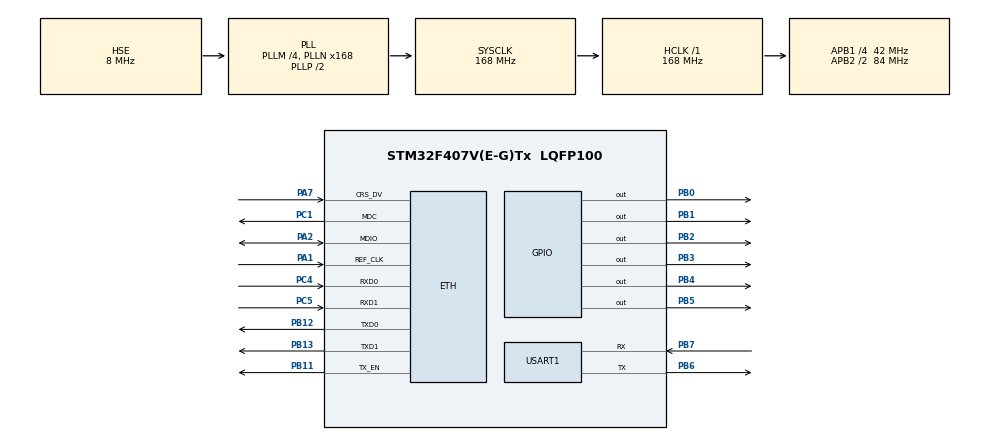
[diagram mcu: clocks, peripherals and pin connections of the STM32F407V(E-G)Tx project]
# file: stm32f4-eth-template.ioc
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ETH.MediaInterface=ETH_MEDIA_INTERFACE_RMII
LWIP.GATEWAY_ADDRESS=192.168.000.001
LWIP.IP_ADDRESS=192.168.000.122
LWIP.LWIP_DBG_OFF=0x00U
LWIP.LWIP_DBG_ON=0x80U
LWIP.LWIP_DHCP=0
LWIP.LWIP_FIONREAD_LINUXMODE=0
LWIP.LWIP_NETCONN=0
LWIP.LWIP_NETCONN_FULLDUPLEX=0
LWIP.LWIP_NETCONN_SEM_PER_THREAD=0
LWIP.LWIP_NETIF_LINK_CALLBACK=1
LWIP.LWIP_POSIX_SOCKETS_IO_NAMES=0
LWIP.LWIP_SOCKET=0
LWIP.LWIP_SOCKET_SET_ERRNO=0
LWIP.LWIP_SO_LINGER=0
LWIP.LWIP_SO_RCVBUF=0
LWIP.LWIP_SO_RCVTIMEO=0
LWIP.LWIP_SO_SNDRCVTIMEO_NONSTANDARD=0
LWIP.LWIP_SO_SNDTIMEO=0
LWIP.LWIP_TCPIP_TIMEOUT=0
LWIP.LWIP_TCP_KEEPALIVE=0
LWIP.LWIP_UDP=0
LWIP.MEM_SIZE=20000
LWIP.NETMASK_ADDRESS=255.255.255.000
LWIP.PBUF_POOL_BUFSIZE=1600
LWIP.SO_REUSE=0
LWIP.SO_REUSE_RXTOALL=0
LWIP.TCP_MSS=1460
LWIP.TCP_QUEUE_OOSEQ=0
LWIP.Version=v2.0.0_Cube
Mcu.Family=STM32F4
Mcu.Name=STM32F407V(E-G)Tx
Mcu.Package=LQFP100
NVIC.ETH_IRQn=true\:0\:0\:false\:false\:true
NVIC.ETH_WKUP_IRQn=true\:0\:0\:false\:false\:true
NVIC.PriorityGroup=NVIC_PRIORITYGROUP_4
PA1.Mode=RMII
PA1.Signal=ETH_REF_CLK
PA2.Mode=RMII
PA2.Signal=ETH_MDIO
PA7.Mode=RMII
PA7.Signal=ETH_CRS_DV
PB0.Signal=GPIO_Output
PB1.Signal=GPIO_Output
PB11.Mode=RMII
PB11.Signal=ETH_TX_EN
PB12.Mode=RMII
PB12.Signal=ETH_TXD0
PB13.Mode=RMII
PB13.Signal=ETH_TXD1
PB2.Signal=GPIO_Output
PB3.Signal=GPIO_Output
PB4.Signal=GPIO_Output
PB5.Signal=GPIO_Output
PB6.Mode=Asynchronous
PB6.Signal=USART1_TX
PB7.Mode=Asynchronous
PB7.Signal=USART1_RX
PC1.Mode=RMII
PC1.Signal=ETH_MDC
PC4.Mode=RMII
PC4.Signal=ETH_RXD0
PC5.Mode=RMII
PC5.Signal=ETH_RXD1
PH0-OSC_IN.Mode=HSE-External-Oscillator
PH0-OSC_IN.Signal=RCC_OSC_IN
PH1-OSC_OUT.Mode=HSE-External-Oscillator
PH1-OSC_OUT.Signal=RCC_OSC_OUT
ProjectManager.HeapSize=0x200
ProjectManager.StackSize=0x400
ProjectManager.TargetToolchain=EWARM
RCC.48MHZClocksFreq_Value=84000000
RCC.AHBFreq_Value=168000000
RCC.APB1CLKDivider=RCC_HCLK_DIV4
RCC.APB1Freq_Value=42000000
RCC.APB1TimFreq_Value=84000000
RCC.APB2CLKDivider=RCC_HCLK_DIV2
RCC.APB2Freq_Value=84000000
RCC.APB2TimFreq_Value=168000000
RCC.ClockTypeHCLK=RCC_CLOCKTYPE_HCLK
RCC.ClockTypePCLK1=RCC_CLOCKTYPE_PCLK1
RCC.ClockTypePCLK2=RCC_CLOCKTYPE_PCLK2
RCC.ClockTypeSysClk=RCC_CLOCKTYPE_SYSCLK
RCC.CortexFreq_Value=168000000
RCC.EnableExtClockForI2S=false
RCC.EnableHSE=true
RCC.EnableHSERTCDevisor=false
RCC.EnableLSE=false
RCC.EnableLSERTC=false
RCC.ExtClockEnable=false
RCC.HCLKFreq_Value=168000000
RCC.HSEState=RCC_HSE_ON
RCC.HSE_VALUE=8000000
RCC.HSIState=RCC_HSI_OFF
RCC.HSI_VALUE=16000000
RCC.I2SEnable=false
RCC.IWDGEnable=false
RCC.LSE_VALUE=32768
RCC.LSIState=RCC_LSI_OFF
RCC.MCO1OutPutEnable=false
RCC.MCO2OutPutEnable=false
RCC.OscillatorTypeHSE=RCC_OSCILLATORTYPE_HSE
RCC.PLLM=4
RCC.PLLN=168
RCC.PLLSource=RCC_PLLSOURCE_HSE
RCC.PLLSourceVirtual=RCC_PLLSOURCE_HSE
RCC.PLLState=RCC_PLL_ON
RCC.RNGEnable=false
RCC.RTCEnable=false
RCC.SDIOEnable=false
RCC.SYSCLKFreq_VALUE=168000000
RCC.SYSCLKSource=RCC_SYSCLKSOURCE_PLLCLK
RCC.USBFSEnable=false
RCC.USBHSEnable=false
RCC.VCOOutputFreq_Value=336000000
USART1.HwFlowCtl-Asynchronous=UART_HWCONTROL_NONE
USART1.VirtualMode=VM_ASYNC
VP_LWIP_VS_Enabled.Mode=Enabled
board=stm32f4-eth-template

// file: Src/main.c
/**
  ******************************************************************************
  * File Name          : main.c
  * Description        : Main program body
  ******************************************************************************
  *
  * Copyright (c) 2017 STMicroelectronics International N.V.
  * All rights reserved.
  *
  * Redistribution and use in source and binary forms, with or without
  * modification, are permitted, provided that the following conditions are met:
  *
  * 1. Redistribution of source code must retain the above copyright notice,
  *    this list of conditions and the following disclaimer.
  * 2. Redistributions in binary form must reproduce the above copyright notice,
  *    this list of conditions and the following disclaimer in the documentation
  *    and/or other materials provided with the distribution.
  * 3. Neither the name of STMicroelectronics nor the names of other
  *    contributors to this software may be used to endorse or promote products
  *    derived from this software without specific written permission.
  * 4. This software, including modifications and/or derivative works of this
  *    software, must execute solely and exclusively on microcontroller or
  *    microprocessor devices manufactured by or for STMicroelectronics.
  * 5. Redistribution and use of this software other than as permitted under
  *    this license is void and will automatically terminate your rights under
  *    this license.
  *
  * THIS SOFTWARE IS PROVIDED BY STMICROELECTRONICS AND CONTRIBUTORS "AS IS"
  * AND ANY EXPRESS, IMPLIED OR STATUTORY WARRANTIES, INCLUDING, BUT NOT
  * LIMITED TO, THE IMPLIED WARRANTIES OF MERCHANTABILITY, FITNESS FOR A
  * PARTICULAR PURPOSE AND NON-INFRINGEMENT OF THIRD PARTY INTELLECTUAL PROPERTY
  * RIGHTS ARE DISCLAIMED TO THE FULLEST EXTENT PERMITTED BY LAW. IN NO EVENT
  * SHALL STMICROELECTRONICS OR CONTRIBUTORS BE LIABLE FOR ANY DIRECT, INDIRECT,
  * INCIDENTAL, SPECIAL, EXEMPLARY, OR CONSEQUENTIAL DAMAGES (INCLUDING, BUT NOT
  * LIMITED TO, PROCUREMENT OF SUBSTITUTE GOODS OR SERVICES; LOSS OF USE, DATA,
  * OR PROFITS; OR BUSINESS INTERRUPTION) HOWEVER CAUSED AND ON ANY THEORY OF
  * LIABILITY, WHETHER IN CONTRACT, STRICT LIABILITY, OR TORT (INCLUDING
  * NEGLIGENCE OR OTHERWISE) ARISING IN ANY WAY OUT OF THE USE OF THIS SOFTWARE,
  * EVEN IF ADVISED OF THE POSSIBILITY OF SUCH DAMAGE.
  *
  ******************************************************************************
  */
#include "main.h"
#include "stm32f4xx_hal.h"
#include "lwip.h"
#include "debug_usart.h"

UART_HandleTypeDef huart1;

/* USER CODE BEGIN PV */
/* Private variables ---------------------------------------------------------*/

/* USER CODE END PV */

void SystemClock_Config(void);
void Error_Handler(void);
static void MX_GPIO_Init(void);
static void MX_USART1_UART_Init(void);

/* USER CODE BEGIN PFP */
/* Private function prototypes -----------------------------------------------*/

/* USER CODE END PFP */

/* USER CODE BEGIN 0 */
static void EXTILine4_Config(void)
{
  GPIO_InitTypeDef   GPIO_InitStructure;

  /* Enable GPIOA clock */
  __HAL_RCC_GPIOA_CLK_ENABLE();

  /* Configure PA0 pin as input floating */
  GPIO_InitStructure.Mode = GPIO_MODE_IT_RISING;
  GPIO_InitStructure.Pull = GPIO_NOPULL;//GPIO_PULLDOWN;//GPIO_PULLDOWN
  GPIO_InitStructure.Pin = GPIO_PIN_4;
  HAL_GPIO_Init(GPIOA, &GPIO_InitStructure);

  /* Enable and set EXTI Line0 Interrupt to the lowest priority */
  HAL_NVIC_SetPriority(EXTI4_IRQn, 0, 0);
  HAL_NVIC_EnableIRQ(EXTI4_IRQn);
}

extern struct netif gnetif;
extern __IO uint32_t is_need_polling;

void HAL_GPIO_EXTI_Callback(uint16_t GPIO_Pin)
{
    //netif_set_link_down(&gnetif);
    //printf("link down from interrupt\n");
  //delay_ms(2000);
  uint32_t regvalue = 0;
  //ethernetif_set_link_polling(&gnetif);
  debug(info, "link down signal");

  /* Check whether the link interrupt has occurred or not */
  HAL_ETH_ReadPHYRegister(&heth, PHY_ISFR, &regvalue);

  if((regvalue & PHY_ISFR_INT4) != (uint16_t)RESET)
  {
    /* Read PHY_SR*/
    HAL_ETH_ReadPHYRegister(&heth, PHY_BSR, &regvalue);

    /* Check whether the link is up or down*/
    if((regvalue & PHY_LINKED_STATUS)!= (uint16_t)RESET)
    {
      debug(info, "link down not confirmed");
    }
    else
    {
       netif_set_link_down(&gnetif);
       is_need_polling = 1;
       debug(info, "link down confirmed");
    }
  }
}

/* USER CODE END 0 */

int main(void)
{

  /* MCU Configuration----------------------------------------------------------*/

  /* Reset of all peripherals, Initializes the Flash interface and the Systick. */
  HAL_Init();

  /* Configure the system clock */
  SystemClock_Config();

  /* Initialize all configured peripherals */
  MX_GPIO_Init();
  MX_USART1_UART_Init();

  MX_LWIP_Init();
  EXTILine4_Config();
  debug(info, "start.");
  //HAL_NVIC_DisableIRQ(SysTick_IRQn);
  /* USER CODE BEGIN 2 */

  tcp_echoserver_init();
  /* USER CODE END 2 */

  //while(1)
  //{test_rect();}
  /* Infinite loop */
  /* USER CODE BEGIN WHILE */
  vRegisterSampleCLICommands();
  while (1)
  {
     prvUARTCommandConsoleTask();
  /* USER CODE END WHILE */
    //if (HAL_ETH_CheckFrameReceived())
    //{
      /* process received ethernet packet*/
    //  LwIP_Pkt_Handle();
    //}
    /* handle periodic timers for LwIP*/
    /*
    HAL_GPIO_WritePin(GPIOD, GPIO_PIN_1, GPIO_PIN_RESET);
    LwIP_Periodic_Handle(sys_now());
    HAL_GPIO_WritePin(GPIOD, GPIO_PIN_1, GPIO_PIN_SET);
    */
  }

}

/** System Clock Configuration
*/
void SystemClock_Config(void)
{

  RCC_OscInitTypeDef RCC_OscInitStruct;
  RCC_ClkInitTypeDef RCC_ClkInitStruct;

    /**Configure the main internal regulator output voltage
    */
  __HAL_RCC_PWR_CLK_ENABLE();

  __HAL_PWR_VOLTAGESCALING_CONFIG(PWR_REGULATOR_VOLTAGE_SCALE1);

    /**Initializes the CPU, AHB and APB busses clocks
    */
  RCC_OscInitStruct.OscillatorType = RCC_OSCILLATORTYPE_HSE;
  RCC_OscInitStruct.HSEState = RCC_HSE_ON;
  RCC_OscInitStruct.PLL.PLLState = RCC_PLL_ON;
  RCC_OscInitStruct.PLL.PLLSource = RCC_PLLSOURCE_HSE;
  RCC_OscInitStruct.PLL.PLLM = 4;
  RCC_OscInitStruct.PLL.PLLN = 168;
  RCC_OscInitStruct.PLL.PLLP = RCC_PLLP_DIV2;
  RCC_OscInitStruct.PLL.PLLQ = 4;
  if (HAL_RCC_OscConfig(&RCC_OscInitStruct) != HAL_OK)
  {
    Error_Handler();
  }

    /**Initializes the CPU, AHB and APB busses clocks
    */
  RCC_ClkInitStruct.ClockType = RCC_CLOCKTYPE_HCLK|RCC_CLOCKTYPE_SYSCLK
                              |RCC_CLOCKTYPE_PCLK1|RCC_CLOCKTYPE_PCLK2;
  RCC_ClkInitStruct.SYSCLKSource = RCC_SYSCLKSOURCE_PLLCLK;
  RCC_ClkInitStruct.AHBCLKDivider = RCC_SYSCLK_DIV1;
  RCC_ClkInitStruct.APB1CLKDivider = RCC_HCLK_DIV4;
  RCC_ClkInitStruct.APB2CLKDivider = RCC_HCLK_DIV2;

  if (HAL_RCC_ClockConfig(&RCC_ClkInitStruct, FLASH_LATENCY_5) != HAL_OK)
  {
    Error_Handler();
  }

    /**Configure the Systick interrupt time
    */
  HAL_SYSTICK_Config(HAL_RCC_GetHCLKFreq()/1000);

    /**Configure the Systick
    */
  HAL_SYSTICK_CLKSourceConfig(SYSTICK_CLKSOURCE_HCLK);

  /* SysTick_IRQn interrupt configuration */
  HAL_NVIC_SetPriority(SysTick_IRQn, 5, 0);
}

/* USART1 init function */
static void MX_USART1_UART_Init(void)
{

  huart1.Instance = USART1;
  huart1.Init.BaudRate = 115200;
  huart1.Init.WordLength = UART_WORDLENGTH_8B;
  huart1.Init.StopBits = UART_STOPBITS_1;
  huart1.Init.Parity = UART_PARITY_NONE;
  huart1.Init.Mode = UART_MODE_TX_RX;
  huart1.Init.HwFlowCtl = UART_HWCONTROL_NONE;
  huart1.Init.OverSampling = UART_OVERSAMPLING_16;
  if (HAL_UART_Init(&huart1) != HAL_OK)
  {
    Error_Handler();
  }
  LL_USART_EnableIT_RXNE(USART1);
  LL_USART_EnableIT_ERROR(USART1);

}

/** Configure pins as
        * Analog
        * Input
        * Output
        * EVENT_OUT
        * EXTI
*/
static void MX_GPIO_Init(void)
{

  GPIO_InitTypeDef GPIO_InitStruct;

  /* GPIO Ports Clock Enable */
  __HAL_RCC_GPIOH_CLK_ENABLE();
  __HAL_RCC_GPIOC_CLK_ENABLE();
  __HAL_RCC_GPIOA_CLK_ENABLE();
  __HAL_RCC_GPIOB_CLK_ENABLE();
  __HAL_RCC_GPIOD_CLK_ENABLE();

  /*Configure GPIO pin Output Level */
  HAL_GPIO_WritePin(GPIOD, GPIO_PIN_8|GPIO_PIN_9|GPIO_PIN_10|GPIO_PIN_11
                          |GPIO_PIN_12|GPIO_PIN_13, GPIO_PIN_RESET);

  /*Configure GPIO pins : PB0 PB1 PB2 PB3
                           PB4 PB5 */
  GPIO_InitStruct.Pin = GPIO_PIN_8|GPIO_PIN_9|GPIO_PIN_10|GPIO_PIN_11
                          |GPIO_PIN_12|GPIO_PIN_13;
  GPIO_InitStruct.Mode = GPIO_MODE_OUTPUT_PP;
  GPIO_InitStruct.Pull = GPIO_NOPULL;
  GPIO_InitStruct.Speed = GPIO_SPEED_FREQ_LOW;
  HAL_GPIO_Init(GPIOD, &GPIO_InitStruct);

    /*Configure GPIO pin Output Level */
  HAL_GPIO_WritePin(GPIOD, GPIO_PIN_1, GPIO_PIN_RESET);

  /*Configure GPIO pins : PB0 PB1 PB2 PB3
                           PB4 PB5 */
  GPIO_InitStruct.Pin = GPIO_PIN_1;
  GPIO_InitStruct.Mode = GPIO_MODE_OUTPUT_PP;
  GPIO_InitStruct.Pull = GPIO_NOPULL; //GPIO_PULLDOWN
  GPIO_InitStruct.Speed = GPIO_SPEED_FREQ_LOW;
  HAL_GPIO_Init(GPIOD, &GPIO_InitStruct);

}

void Error_Handler(void)
{
  while(1)
  {
  }
}

/************************ (C) COPYRIGHT STMicroelectronics *****END OF FILE****/
